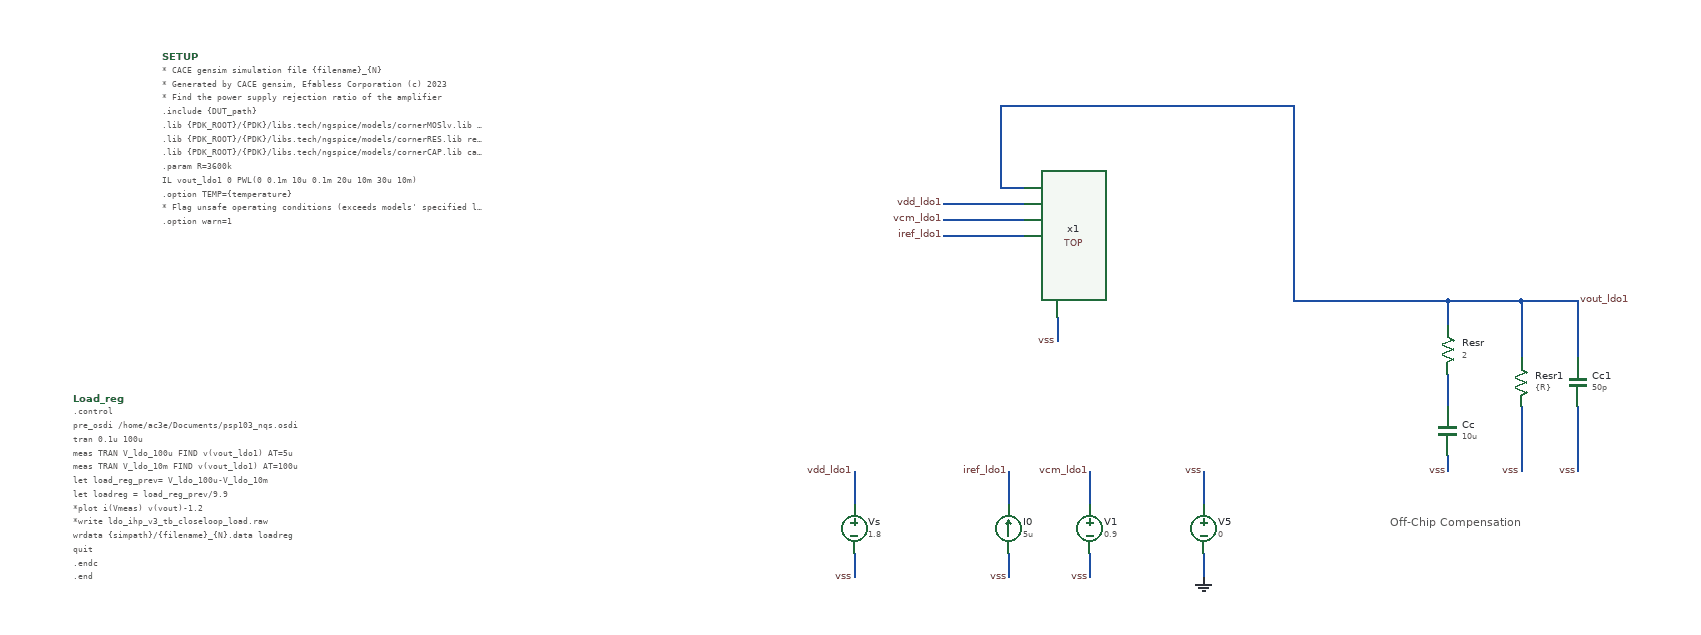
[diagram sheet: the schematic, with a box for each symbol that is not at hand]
v {xschem version=3.4.5 file_version=1.2
}
G {}
K {}
V {}
S {}
E {}
T {Off-Chip Compensation
} 710 40 3 0 0.4 0.4 {}
N 240 -10 240 30 {
lab=iref_ldo1}
N 480 90 480 120 {
lab=GND}
N 340 90 340 120 {
lab=vss}
N 240 90 240 120 {
lab=vss}
N 480 -10 480 30 {
lab=vss}
N 340 -10 340 30 {
lab=vcm_ldo1}
N 780 -220 780 -190 {
lab=vout_ldo1}
N 780 -130 780 -90 {
lab=#net1}
N 780 -30 780 -10 {
lab=vss}
N 160 -340 260 -340 {
lab=vdd_ldo1}
N 160 -300 260 -300 {
lab=iref_ldo1}
N 160 -320 260 -320 {
lab=vcm_ldo1}
N 300 -200 300 -170 {
lab=vss}
N 590 -220 780 -220 {
lab=vout_ldo1}
N 870 -220 870 -150 {
lab=vout_ldo1}
N 780 -220 870 -220 {
lab=vout_ldo1}
N 870 -90 870 -10 {
lab=vss}
N 940 -220 940 -150 {
lab=vout_ldo1}
N 870 -220 940 -220 {
lab=vout_ldo1}
N 940 -90 940 -10 {
lab=vss}
N 590 -460 590 -220 {
lab=vout_ldo1}
N 230 -460 590 -460 {
lab=vout_ldo1}
N 230 -460 230 -360 {
lab=vout_ldo1}
N 230 -360 260 -360 {
lab=vout_ldo1}
N 50 90 50 120 {
lab=vss}
N 50 -10 50 30 {
lab=vdd_ldo1}
C {devices/vsource.sym} 340 60 0 0 {name=V1 value=0.9 savecurrent=false}
C {devices/vsource.sym} 480 60 0 0 {name=V5 value=0 savecurrent=false}
C {devices/isource.sym} 240 60 2 0 {name=I0 value=5u}
C {devices/lab_pin.sym} 340 120 0 0 {name=p2 sig_type=std_logic lab=vss}
C {devices/gnd.sym} 480 120 0 0 {name=l1 lab=GND}
C {devices/lab_pin.sym} 480 -10 0 0 {name=p5 sig_type=std_logic lab=vss}
C {devices/lab_pin.sym} 300 -170 3 0 {name=p9 sig_type=std_logic lab=vss}
C {devices/lab_pin.sym} 160 -320 0 0 {name=p13 sig_type=std_logic lab=vcm_ldo1}
C {devices/lab_pin.sym} 240 120 0 0 {name=p14 sig_type=std_logic lab=vss}
C {devices/lab_pin.sym} 940 -220 2 0 {name=p15 sig_type=std_logic lab=vout_ldo1}
C {devices/lab_pin.sym} 240 -10 0 0 {name=p12 sig_type=std_logic lab=iref_ldo1}
C {devices/lab_pin.sym} 160 -300 0 0 {name=p17 sig_type=std_logic lab=iref_ldo1}
C {devices/lab_pin.sym} 340 -10 0 0 {name=p18 sig_type=std_logic lab=vcm_ldo1}
C {devices/lab_pin.sym} 160 -340 0 0 {name=p19 sig_type=std_logic lab=vdd_ldo1}
C {devices/capa.sym} 780 -60 0 0 {name=Cc
m=1
value=10u
footprint=1206
device="ceramic capacitor"}
C {devices/res.sym} 780 -160 0 0 {name=Resr
value=2
footprint=1206
device=resistor
m=1}
C {devices/lab_pin.sym} 780 -10 0 0 {name=p4 sig_type=std_logic lab=vss}
C {devices/title.sym} -190 370 0 0 {name=l2 author="Daniel Arevalos"}
C {devices/lab_pin.sym} 870 -10 0 0 {name=p1 sig_type=std_logic lab=vss}
C {devices/res.sym} 870 -120 0 0 {name=Resr1
value=\{R\}
footprint=1206
device=resistor
m=1}
C {devices/capa.sym} 940 -120 0 0 {name=Cc1
m=1
value=50p
footprint=1206
device="ceramic capacitor"}
C {devices/lab_pin.sym} 940 -10 0 0 {name=p3 sig_type=std_logic lab=vss}
C {devices/code_shown.sym} -800 -520 0 0 {name=SETUP only_toplevel=false value="* CACE gensim simulation file \{filename\}_\{N\}
* Generated by CACE gensim, Efabless Corporation (c) 2023
* Find the power supply rejection ratio of the amplifier

.include \{DUT_path\}

.lib \{PDK_ROOT\}/\{PDK\}/libs.tech/ngspice/models/cornerMOSlv.lib mos_\{corner\}
.lib \{PDK_ROOT\}/\{PDK\}/libs.tech/ngspice/models/cornerRES.lib res_typ
.lib \{PDK_ROOT\}/\{PDK\}/libs.tech/ngspice/models/cornerCAP.lib cap_typ

.param R=3600k

IL vout_ldo1 0 PWL(0 0.1m 10u 0.1m 20u 10m 30u 10m)

.option TEMP=\{temperature\}
* Flag unsafe operating conditions (exceeds models' specified limits)
.option warn=1
"}
C {devices/vsource.sym} 50 60 0 0 {name=Vs value="1.8" savecurrent=false}
C {devices/lab_pin.sym} 50 120 0 0 {name=p6 sig_type=std_logic lab=vss}
C {devices/lab_pin.sym} 50 -10 0 0 {name=p7 sig_type=std_logic lab=vdd_ldo1}
C {devices/code_shown.sym} -910 -100 0 0 {name=Load_reg only_toplevel=false 

value="
.control
pre_osdi /home/ac3e/Documents/psp103_nqs.osdi
tran 0.1u 100u
meas TRAN V_ldo_100u FIND v(vout_ldo1) AT=5u
meas TRAN V_ldo_10m FIND v(vout_ldo1) AT=100u
let load_reg_prev= V_ldo_100u-V_ldo_10m
let loadreg = load_reg_prev/9.9
*plot i(Vmeas) v(vout)-1.2
*write ldo_ihp_v3_tb_closeloop_load.raw
wrdata \{simpath\}/\{filename\}_\{N\}.data loadreg
quit
.endc

.end
"}
C {/home/ac3e/Documents/ihp_design/cace/TOP.sym} 360 -300 0 0 {name=x1}
